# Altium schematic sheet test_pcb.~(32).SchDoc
size A4; SheetNumber: 1; SheetTotal: 1

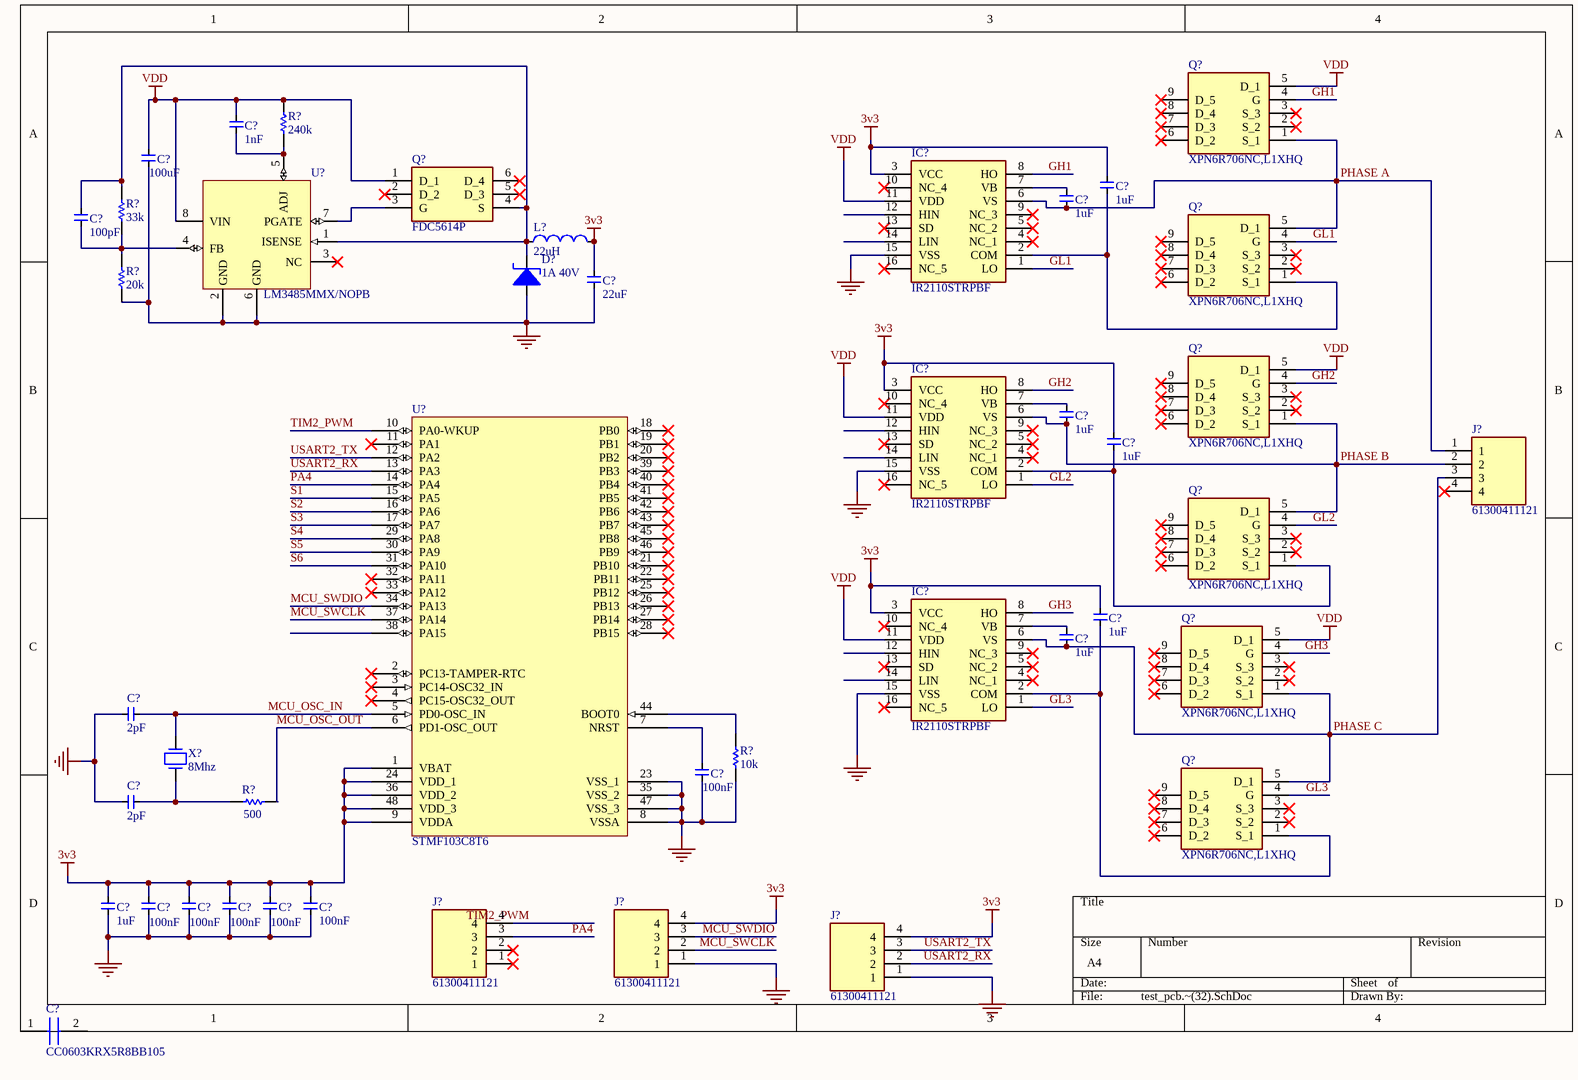
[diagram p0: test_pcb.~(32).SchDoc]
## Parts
(Parts that share a designator on the sheet are numbered #1, #2 ... from top to bottom, then left to right.)
C?#1  1nF  [C0402C104J4RACTU]
C?#2  100uF  [GRM31x]
C?#3  1uF  [CAPC1608X90N]
C?#4  1uF  [GRM033D70J224ME01D]
C?#5  100pF
C?#6  22uF  [CAPC2012X145N]
C?#7  1uF  [GRM033D70J224ME01D]
C?#8  1uF  [GRM033D70J224ME01D]
C?#9  1uF  [GRM033D70J224ME01D]
C?#10  1uF  [GRM033D70J224ME01D]
C?#11  2pF
C?#12  100nF
C?#13  2pF
C?#14  1uF
C?#15  100nF
C?#16  100nF
C?#17  100nF
C?#18  100nF
C?#19  100nF
C?#20  CC0603KRX5R8BB105  [CAPC1608X90N]
D?  1A 40V  [DIOM5026X262N]
IC?#1  IR2110STRPBF  [SOIC127P1032X265-16N]
IC?#2  IR2110STRPBF  [SOIC127P1032X265-16N]
IC?#3  IR2110STRPBF  [SOIC127P1032X265-16N]
J?#1  61300411121
J?#2  61300411121
J?#3  61300411121
J?#4  61300411121
L?  22uH  [INDPM7166X300N]
Q?#1  XPN6R706NC,L1XHQ  [XPN6R706NCL1XHQ]
Q?#2  FDC5614P  [SOT95P280X110-6N]
Q?#3  XPN6R706NC,L1XHQ  [XPN6R706NCL1XHQ]
Q?#4  XPN6R706NC,L1XHQ  [XPN6R706NCL1XHQ]
Q?#5  XPN6R706NC,L1XHQ  [XPN6R706NCL1XHQ]
Q?#6  XPN6R706NC,L1XHQ  [XPN6R706NCL1XHQ]
Q?#7  XPN6R706NC,L1XHQ  [XPN6R706NCL1XHQ]
R?#1  240k  [ERJ3EKF1000V]
R?#2  33k  [ERA3AEB101V]
R?#3  20k  [ERJ2RKD1004X]
R?#4  10k
R?#5  500
U?#1  LM3485MMX/NOPB  [SOP65P490X110-8N]
U?#2  STMF103C8T6
X?  8Mhz

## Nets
3v3: C?#3.2 C?#6.2 C?#8.2 C?#9.2 C?#14.2 C?#15.2 C?#16.2 C?#17.2 C?#18.2 C?#19.2 IC?#1.3(VCC) IC?#2.3(VCC) IC?#3.3(VCC) J?#3.4 J?#4.4 L?.2 U?#2.1(VBAT) U?#2.9(VDDA) U?#2.24(VDD_1) U?#2.36(VDD_2) U?#2.48(VDD_3)
GND: C?#2.1 C?#6.1 C?#11.1 C?#12.1 C?#13.1 C?#14.1 C?#15.1 C?#16.1 C?#17.1 C?#18.1 C?#19.1 D?.+ IC?#1.15(VSS) IC?#2.15(VSS) IC?#3.15(VSS) J?#3.1 J?#4.1 R?#3.4 R?#4.4 U?#1.2(GND) U?#1.6(GND) U?#2.8(VSSA) U?#2.23(VSS_1) U?#2.35(VSS_2) U?#2.47(VSS_3)
VDD: C?#1.2 C?#2.2 IC?#1.11(VDD) IC?#2.11(VDD) IC?#3.11(VDD) Q?#1.5(D_1) Q?#2.1(D_1) Q?#4.5(D_1) Q?#6.5(D_1) R?#1.2 U?#1.8(VIN)
GH1: IC?#1.8(HO) Q?#1.4(G)
GH2: IC?#2.8(HO) Q?#4.4(G)
GH3: IC?#3.8(HO) Q?#6.4(G)
GL1: IC?#1.1(LO) Q?#3.4(G)
GL2: IC?#2.1(LO) Q?#5.4(G)
GL3: IC?#3.1(LO) Q?#7.4(G)
MCU_OSC_IN: C?#11.2 U?#2.5(PD0-OSC_IN) X?.2
MCU_OSC_OUT: R?#5.2 U?#2.6(PD1-OSC_OUT)
MCU_SWCLK: J?#3.2 U?#2.37(PA14)
MCU_SWDIO: J?#3.3 U?#2.34(PA13)
PA4: J?#2.3 U?#2.14(PA4)
PHASE A: C?#4.1 IC?#1.6(VS) J?#1.1 Q?#1.1(S_1) Q?#3.5(D_1)
PHASE B: C?#7.1 IC?#2.6(VS) J?#1.2 Q?#4.1(S_1) Q?#5.5(D_1)
PHASE C: C?#10.1 IC?#3.6(VS) J?#1.3 Q?#6.1(S_1) Q?#7.5(D_1)
S1: U?#2.15(PA5)
S2: U?#2.16(PA6)
S3: U?#2.17(PA7)
S4: U?#2.29(PA8)
S5: U?#2.30(PA9)
S6: U?#2.31(PA10)
TIM2_PWM: J?#2.4 U?#2.10(PA0-WKUP)
USART2_RX: J?#4.2 U?#2.13(PA3)
USART2_TX: J?#4.3 U?#2.12(PA2)
NetC?#1_1: C?#1.1 R?#1.4 U?#1.5(ADJ)
NetC?#3_1: C?#3.1 IC?#1.2(COM) Q?#3.1(S_1)
NetC?#4_2: C?#4.2 IC?#1.7(VB)
NetC?#5_1: C?#5.1 R?#2.4 R?#3.2 U?#1.4(FB)
NetC?#5_2: C?#5.2 D?.- L?.1 Q?#2.4(S) R?#2.2 U?#1.1(ISENSE)
NetC?#7_2: C?#7.2 IC?#2.7(VB)
NetC?#8_1: C?#8.1 IC?#2.2(COM) Q?#5.1(S_1)
NetC?#9_1: C?#9.1 IC?#3.2(COM) Q?#7.1(S_1)
NetC?#10_2: C?#10.2 IC?#3.7(VB)
NetC?#12_2: C?#12.2 U?#2.7(NRST)
NetC?#13_2: C?#13.2 R?#5.4 X?.1
NetQ?#2_3: Q?#2.3(G) U?#1.7(PGATE)
NetR?#4_2: R?#4.2 U?#2.44(BOOT0)

Not connected (* = marked no-connect by the designer): C?#20 1 2; IC?#1 4(NC_1)* 5(NC_2)* 9(NC_3)* 10(NC_4)* 12(HIN) 13(SD)* 14(LIN) 16(NC_5)*; IC?#2 4(NC_1)* 5(NC_2)* 9(NC_3)* 10(NC_4)* 12(HIN) 13(SD)* 14(LIN) 16(NC_5)*; IC?#3 4(NC_1)* 5(NC_2)* 9(NC_3)* 10(NC_4)* 12(HIN) 13(SD)* 14(LIN) 16(NC_5)*; J?#1 4*; J?#2 1* 2*; Q?#1 2(S_2)* 3(S_3)* 6(D_2)* 7(D_3)* 8(D_4)* 9(D_5)*; Q?#2 2(D_2)* 5(D_3)* 6(D_4)*; Q?#3 2(S_2)* 3(S_3)* 6(D_2)* 7(D_3)* 8(D_4)* 9(D_5)*; Q?#4 2(S_2)* 3(S_3)* 6(D_2)* 7(D_3)* 8(D_4)* 9(D_5)*; Q?#5 2(S_2)* 3(S_3)* 6(D_2)* 7(D_3)* 8(D_4)* 9(D_5)*; Q?#6 2(S_2)* 3(S_3)* 6(D_2)* 7(D_3)* 8(D_4)* 9(D_5)*; Q?#7 2(S_2)* 3(S_3)* 6(D_2)* 7(D_3)* 8(D_4)* 9(D_5)*; U?#1 3(NC)*; U?#2 2(PC13-TAMPER-RTC)* 3(PC14-OSC32_IN)* 4(PC15-OSC32_OUT)* 11(PA1)* 18(PB0)* 19(PB1)* 20(PB2)* 21(PB10)* 22(PB11)* 25(PB12)* 26(PB13)* 27(PB14)* 28(PB15)* 32(PA11)* 33(PA12)* 38(PA15) 39(PB3)* 40(PB4)* 41(PB5)* 42(PB6)* 43(PB7)* 45(PB8)* 46(PB9)*

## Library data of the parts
C?#1 = C0402C102J5GECTU: Ceramic Capacitor, Multilayer, Ceramic, 50V, 5% +Tol, 5% -Tol, C0G, -/+30ppm/Cel TC, 0.001uF, Surface Mount, 0402; Manufacturer: KEMET
C?#2 = GRM31CR60J107MEA8K: Ceramic Capacitor, Multilayer, Ceramic, 6.3V, 20% +Tol, 20% -Tol, X5R, 15% TC, 100uF, Surface Mount, 1206; Manufacturer: Murata
C?#3 = CC0603KRX5R8BB105: Ceramic Capacitor, Multilayer, Ceramic, 25V, 10% +Tol, 10% -Tol, X5R, 15% TC, 1uF, Surface Mount, 0603; Manufacturer: Yageo; Multilayer: Yes
C?#4 C?#7-C?#10 C?#14 = GRM033R60J105MEA2D: Ceramic Capacitor, Multilayer, Ceramic, 6.3V, 20% +Tol, 20% -Tol, X5R, 15% TC, 1uF, Surface Mount, 0201; Manufacturer: Murata; Multilayer: Yes
C?#5 = GRM0335C1H101JA01D: Ceramic Capacitor, Multilayer, Ceramic, 50V, 5% +Tol, 5% -Tol, C0G, 30ppm/Cel TC, 0.0001uF, Surface Mount, 0201; Manufacturer: Murata; Multilayer: Yes
C?#6 = C2012X5R1V226M125AC: Ceramic Capacitor, Multilayer, Ceramic, 35V, 20% +Tol, 20% -Tol, X5R, 15% TC, 22uF, Surface Mount, 0805; Manufacturer: TDK; Multilayer: Yes
C?#11 C?#13 = GJM0335C1E2R0BB01D: Ceramic Capacitor, Multilayer, Ceramic, 25V, 5% +Tol, 5% -Tol, C0G, 30ppm/Cel TC, 0.000002uF, Surface Mount, 0201; Manufacturer: Murata; Multilayer: Yes
C?#12 C?#15-C?#19 = GRM033C80J104KE15D: Ceramic Capacitor, Multilayer, Ceramic, 6.3V, 10% +Tol, 10% -Tol, X6S, 22% TC, 0.1uF, Surface Mount, 0201; Manufacturer: Murata; Multilayer: Yes
C?#20 = CC0603KRX5R8BB105: Capacitor; Manufacturer_Name: KEMET
D? = SS14: Rectifier Diode, Schottky, 1 Phase, 1 Element, 1A, 40V V(RRM), Silicon, DO-214AC; Manufacturer: ON Semiconductor / Fairchild; Package Body Material: Plastic; Forward Voltage: 500mV; Non-rep Pk Forward Current-Max: 30A; Number of Elements: 1; Additional Feature: FREE WHEELING DIODE; Max Power Dissipation: 1.1W; Qualification Status: Not Qualified
IC?#1-IC?#3 = IR2110STRPBF: Half Bridge Based MOSFET Driver, 2.5A, CMOS, PDSO16; Manufacturer: Infineon; Package Body Material: Plastic; High Side Driver: Yes; Channels: 1; Supply Voltage1-Max: 520V; Supply Voltage1-Min: 6V; Max Supply Voltage: 20V; Min Supply Voltage: 3.3V; Nominal Supply Voltage: 15V; Turn-Off Delay Time: 0.125us; Turn-On Delay Time: 0.15us; Package Equivalence Code: SOP16,.4; Time @ Peak Reflow Temperature-Max (s): 30s; Qualification Status: Not Qualified
L? = ECS-MPIL0630-220MC: General Purpose Inductor, 22uH, 20%, 1 Element, Ferrite-Core, SMD, 2826; Manufacturer: ECS International
Q?#1 Q?#3-Q?#7 = XPN6R706NC,L1XHQ: Mosfet N-ch 60V 40A 8TSON; Manufacturer: Toshiba
Q?#2 = FDC5614P: Small Signal Field-Effect Transistor, 3A I(D), 60V, 1-Element, P-Channel, Silicon, Metal-oxide Semiconductor FET; Manufacturer: ON Semiconductor / Fairchild; Package Body Material: Plastic; Drain-source On Resistance-Max: 105mR; Number of Elements: 1; Operating Mode: ENHANCEMENT MODE; Power Dissipation-Max (Abs): 1.6W; Transistor Application: SWITCHING; Qualification Status: Not Qualified
R?#1 = ERJ-3GEYJ244V: Fixed Resistor, Metal Glaze/thick Film, 0.1W, 240000ohm, 75V, 5% +/-Tol, 200ppm/Cel, Surface Mount, 0603; Manufacturer: Panasonic; Power: 100mW; Rated Temperature: 70°C; Value: 240kR; Temperature Coefficient (ppm/Cel): 200; Package Height: 0.45mm; Package Length: 1.6mm; Package Width: 0.8mm; Reference Standard: AEC-Q200
R?#2 = ERA-3AEB333V: Fixed Resistor, Thin Film, 0.1W, 33000ohm, 75V, 0.1% +/-Tol, 25ppm/Cel, Surface Mount, 0603; Manufacturer: Panasonic; Power: 100mW; Rated Temperature: 85°C; Value: 33kR; Temperature Coefficient (ppm/Cel): 25; Package Height: 0.45mm; Package Length: 1.6mm; Package Width: 0.8mm; Reference Standard: AEC-Q200
R?#3 = ERJ-2RKF2002X: Fixed Resistor, Metal Glaze/thick Film, 0.1W, 20000ohm, 50V, 1% +/-Tol, 100ppm/Cel, Surface Mount, 0402; Manufacturer: Panasonic; Power: 100mW; Rated Temperature: 70°C; Value: 20kR; Temperature Coefficient (ppm/Cel): 100; Package Height: 0.35mm; Package Length: 1mm; Package Width: 0.5mm; Reference Standard: AEC-Q200
R?#4 = RNCP1206FTD10K0: Fixed Resistor, Thin Film, 0.5W, 10000ohm, 200V, 1% +/-Tol, 100ppm/Cel, Surface Mount, 1206; Manufacturer: Stackpole Electronics; Additional Feature: ANTI-SULFUR; Power: 500mW; Rated Temperature: 70°C; Value: 10kR; Temperature Coefficient (ppm/Cel): 100; Package Height: 0.5mm; Package Length: 3.1mm; Package Width: 1.5mm
R?#5 = ERA-2AEB4990X: Fixed Resistor, Thin Film, 0.063W, 499ohm, 50V, 0.1% +/-Tol, 25ppm/Cel, Surface Mount, 0402; Manufacturer: Panasonic; Power: 63mW; Rated Temperature: 85°C; Value: 499R; Working Voltage: 25V; Temperature Coefficient (ppm/Cel): 25; Package Height: 0.35mm; Package Length: 1mm; Package Width: 0.5mm; Reference Standard: AEC-Q200
U?#1 = LM3485MMX/NOPB: Switching Controller, Voltage-mode, 0.1A, 1000kHz Switching Freq-Max, PDSO8; Manufacturer: TI National Semiconductor; Package Body Material: Plastic; Control Technique: HYSTERETIC CURRENT MODE; Max Supply Voltage: 35V; Min Input Voltage: 4.5V; Nominal Supply Voltage: 12V; Channels: 1; Max Output current: 100mA; Package Equivalence Code: TSSOP8,.19; Switcher Configuration: SINGLE; Frequency: 1MHz; Time @ Peak Reflow Temperature-Max (s): 40s; Qualification Status: Not Qualified
U?#2 = STM32F103C8T6_1: ARM Cortex-M3 STM32 F1 Microcontroller 32-Bit 72MHz 64kB FLASH LQFP48 STM32F103C8T6; Manufacturer: STMicroelectronics; Package Body Material: Plastic; Clock Frequency: 16MHz; Number of I/O Lines: 37; Package Equivalence Code: QFP48,.35SQ,20; Power Supplies: 2.5/3.3; Max Supply Current: 50mA; Max Supply Voltage: 3.6V; Min Supply Voltage: 2V; Nominal Supply Voltage: 3.3V; Time @ Peak Reflow Temperature-Max (s): 30s; Peripherals: POR; Interface: I2C; Qualification Status: Not Qualified
X? = H130A-8.000-8-2030-TR: Parallel - Fundamental Quartz Crystal, 8MHz Min, 150MHz Max, 8MHz Nom; Manufacturer: Raltron Electronics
